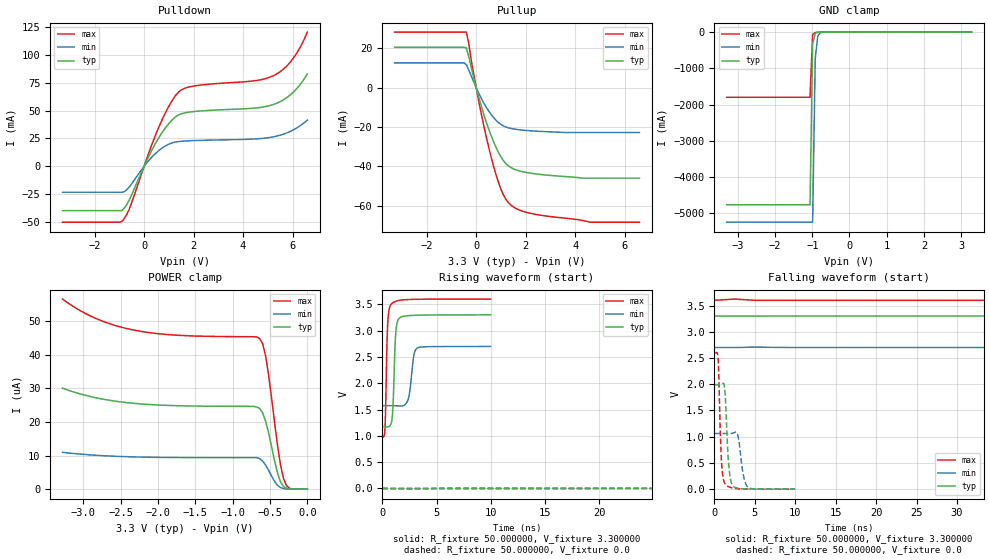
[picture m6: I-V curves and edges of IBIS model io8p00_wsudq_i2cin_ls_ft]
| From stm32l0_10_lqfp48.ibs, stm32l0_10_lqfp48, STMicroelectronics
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|   Model io8p00_wsudq_i2cin_ls_ft
[Model]  io8p00_wsudq_i2cin_ls_ft
Model_type I/O
Polarity   Non-Inverting
Enable   Active-Low
Vinl =   0.990000V
Vinh =   2.310000V
Vmeas =  1.650000V
Cref =   50.000000pF
Rref =   100.000000M
Vref =   0.0V
C_comp   3.020400pF   2.988200pF   3.054500pF
[Temperature Range]   25.000000   0.125000k   -40.000000
[Pullup Reference]   3.300000V   2.700000V   3.600000V
[Pulldown Reference]   0.0V   0.0V   0.0V
[POWER Clamp Reference]   3.300000V   2.700000V   3.600000V
[GND Clamp Reference]   0.0V   0.0V   0.0V
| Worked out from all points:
|   slope of the pulldown table from 0 to 0.495 V, typ, clamps not added: 22.6 ohm
|   slope of the pullup table from 0 to 0.495 V, typ, clamps not added: 23.9 ohm
|   GND clamp passes 1 mA (typ) near -0.64 V on its own axis
|   rising waveform, R_fixture 50.000000, V_fixture 3.300000: 20-80 % time 222ps typ, 369ps min, 183ps max; typ from 1.18 V to 3.3 V
|   rising waveform, R_fixture 50.000000, V_fixture 0.0: 20-80 % time 204ns typ, 426ns min, 99.1ns max; typ from 0 V to 1.99 V
|   falling waveform, R_fixture 50.000000, V_fixture 3.300000: 20-80 % time 191ns typ, 379ns min, 105ns max; typ from 3.3 V to 1.18 V
|   falling waveform, R_fixture 50.000000, V_fixture 0.0: 20-80 % time 405ps typ, 572ps min, 327ps max; typ from 1.99 V to 0 V
[Pulldown]
|Voltage   I(typ)   I(min)   I(max)
-3.3V     -39.83mA   -23.37mA   -50.21mA
-900mV    -39.83mA   -23.37mA   -49.53mA
-600mV    -30.28mA   -18.59mA   -38.45mA
500mV     22.11mA    12.28mA    30.1mA
1V        38.33mA    19.81mA    53.88mA
1.4V      46.1mA     22.18mA    66.72mA
2V        49.07mA    23.02mA    71.93mA
4.4V      52.05mA    24.38mA    76.53mA
5.2V      55.25mA    26.31mA    81.02mA
5.6V      59.18mA    28.57mA    86.57mA
6V        65.78mA    32.24mA    95.97mA
6.6V      82.83mA    41.41mA    120.4mA
[Pullup]
|Voltage   I(typ)   I(min)   I(max)
-3.3V     20.52mA    12.64mA    28.28mA
-400mV    20.25mA    11.77mA    28.28mA
-300mV    15.65mA    8.927mA    22.44mA
-200mV    10.4mA     5.943mA    13.84mA
100mV     -4.685mA   -2.744mA   -6.646mA
600mV     -24.29mA   -13.56mA   -35.12mA
1V        -35.2mA    -18.69mA   -51.63mA
1.2V      -38.62mA   -19.99mA   -56.79mA
1.4V      -40.6mA    -20.72mA   -59.71mA
2.2V      -43.48mA   -21.92mA   -63.91mA
4.6V      -46mA      -22.8mA    -68.41mA
6.6V      -46mA      -22.8mA    -68.41mA
[GND_clamp]
|Voltage   I(typ)   I(min)   I(max)
-3.3V     -4.766A    -5.244A    -1.797A
-1.06V    -4.766A    -5.244A    -1.797A
-990mV    -326.6mA   -5.244A    -67.9mA
-920mV    -28.92mA   -722.1mA   -10.96mA
-850mV    -6.612mA   -104.2mA   -6.532mA
-780mV    -3.464mA   -17.27mA   -4.209mA
-500mV    -57.88uA   -167.8uA   -34.02uA
3.28V     0A         0A         0A
[POWER_clamp]
|Voltage   I(typ)   I(min)   I(max)
-3.28V    30.07uA    10.97uA    56.59uA
-2.84V    27.25uA    10.1uA     50.89uA
-2.32V    25.55uA    9.602uA    47.34uA
-640mV    24.06uA    9.099uA    44.84uA
-600mV    22.76uA    8.364uA    43.37uA
-560mV    20.32uA    7.211uA    39.74uA
-520mV    16.86uA    5.675uA    34.14uA
-400mV    4.841uA    1.145uA    13.1uA
-360mV    2.184uA    477.2nA    7.288uA
-320mV    772.4nA    180.3nA    3.213uA
-240mV    60.03nA    0A         295.3nA
0V        0A         0A         0A
[Ramp]
| variable   typ   min   max
dV/dt_r  1.19496/0.20349u   0.61296/0.42680u   1.55568/98.97032n
dV/dt_f  1.27296/0.19096u   0.63678/0.37937u   1.57856/0.10499u
R_load = 50.000000
[Rising Waveform]
R_fixture= 50.000000
V_fixture= 3.300000
V_fixture_min= 2.700000
V_fixture_max= 3.600000
|time   V(typ)   V(min)   V(max)
0s        1.177V     1.573V     967.3mV
240.2ps   1.176V     1.573V     1.135V
520.5ps   1.173V     1.574V     3.217V
820.8ps   1.244V     1.574V     3.506V
981ps     1.569V     1.574V     3.534V
1.241ns   2.967V     1.572V     3.559V
1.562ns   3.236V     1.568V     3.576V
2.382ns   3.284V     1.699V     3.59V
3.223ns   3.293V     2.67V      3.596V
9.97ns    3.3V       2.7V       3.6V
[Rising Waveform]
R_fixture= 50.000000
V_fixture= 0.0
V_fixture_min= 0.0
V_fixture_max= 0.0
|time   V(typ)   V(min)   V(max)
0s        2.524nV    17.72nV    5.69nV
50.05ns   688.7uV    -21.63uV   86.73mV
100.1ns   75.28mV    12.41uV    913.4mV
162.7ns   438.2mV    6.321mV    1.907V
202.7ns   729.8mV    14.38mV    2.278V
250.2ns   1.059V     49.55mV    2.475V
367.9ns   1.619V     205.5mV    2.576V
503ns     1.881V     442.1mV    2.59V
865.9ns   1.988V     908.5mV    2.592V
1.246us   1.992V     1.062V     2.592V
[Falling Waveform]
R_fixture= 50.000000
V_fixture= 3.300000
V_fixture_min= 2.700000
V_fixture_max= 3.600000
|time   V(typ)   V(min)   V(max)
0s        3.3V       2.7V       3.6V
82.58ns   3.3V       2.7V       3.491V
150.2ns   3.19V      2.7V       2.487V
212.7ns   2.837V     2.697V     1.576V
247.7ns   2.596V     2.687V     1.234V
285.3ns   2.326V     2.665V     1.081V
402.9ns   1.577V     2.534V     992.8mV
513ns     1.314V     2.344V     975.8mV
825.8ns   1.195V     1.79V      967.8mV
1.246us   1.177V     1.573V     967.3mV
[Falling Waveform]
R_fixture= 50.000000
V_fixture= 0.0
V_fixture_min= 0.0
V_fixture_max= 0.0
|time   V(typ)   V(min)   V(max)
0s        1.992V     1.062V     2.592V
440.4ps   1.992V     1.062V     2.509V
860.9ps   1.996V     1.062V     569mV
1.301ns   1.857V     1.062V     105.8mV
1.762ns   477.7mV    1.061V     46.3mV
2.282ns   64.77mV    1.068V     19.81mV
2.883ns   19.1mV     1.029V     7.847mV
3.524ns   7.848mV    313mV      4.636mV
4.164ns   4.058mV    32.89mV    3.148mV
9.97ns    2.524nV    17.72nV    5.69nV
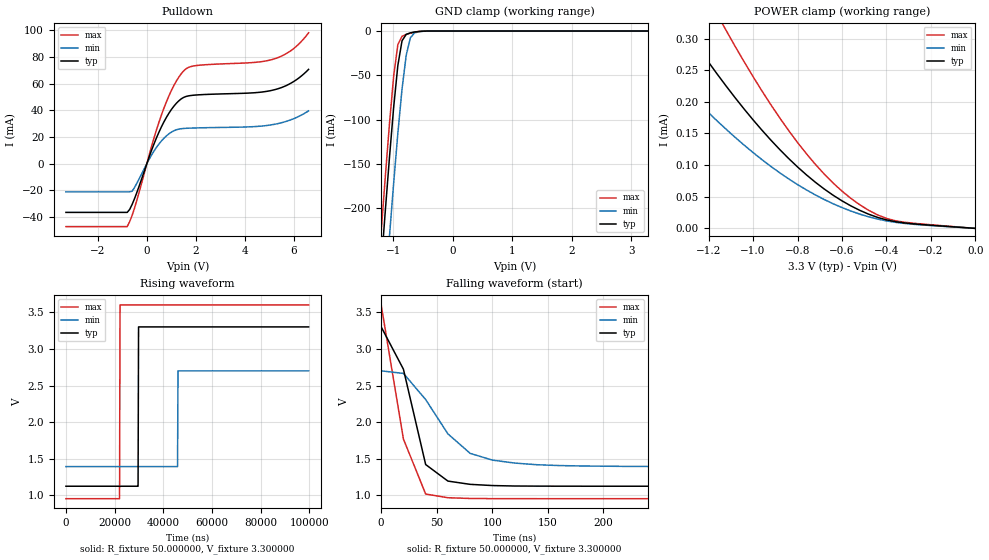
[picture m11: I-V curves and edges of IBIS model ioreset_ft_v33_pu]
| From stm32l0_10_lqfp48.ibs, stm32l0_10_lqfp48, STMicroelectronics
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|   Model ioreset_ft_v33_pu
[Model]  ioreset_ft_v33_pu
Model_type I/O_open_drain
Polarity   Inverting
Enable   Active-High
Vinl =   0.990000V
Vinh =   2.310000V
Vmeas =  1.650000V
Cref =   1.0000000000000001E-7F
Rref =   1.000000k
Vref =   3.300000V
C_comp   2.072900pF   1.973900pF   2.107400pF
[Temperature Range]   25.000000   0.125000k   -40.000000
[Pullup Reference]   3.300000V   2.700000V   3.600000V
[Pulldown Reference]   0.0V   0.0V   0.0V
[POWER Clamp Reference]   3.300000V   2.700000V   3.600000V
[GND Clamp Reference]   0.0V   0.0V   0.0V
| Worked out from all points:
|   slope of the pulldown table from 0 to 0.495 V, typ, clamps not added: 20.9 ohm
|   GND clamp passes 1 mA (typ) near -0.62 V on its own axis
|   rising waveform, R_fixture 50.000000, V_fixture 3.300000: 20-80 % time 120ns typ, 120ns min, 120ns max; typ from 1.12 V to 3.3 V
|   falling waveform, R_fixture 50.000000, V_fixture 3.300000: 20-80 % time 22.8ns typ, 41.3ns min, 21.9ns max; typ from 3.3 V to 1.12 V
[Pulldown]
|Voltage   I(typ)   I(min)   I(max)
-3.3V     -36.46mA   -21.09mA   -47.09mA
-800mV    -36.46mA   -21.09mA   -47.09mA
-600mV    -30.5mA    -20.55mA   -38.69mA
200mV     10.38mA    6.711mA    13.48mA
700mV     31.4mA     19.11mA    41.71mA
1.2V      45.15mA    25.37mA    61.75mA
1.6V      50.35mA    26.5mA     71.06mA
2.1V      51.56mA    26.83mA    73.67mA
4.4V      53.15mA    27.79mA    75.86mA
5.2V      55.35mA    29.47mA    78.49mA
5.9V      60.51mA    33.05mA    84.93mA
6.6V      70.63mA    39.56mA    98mA
[GND_clamp]
|Voltage   I(typ)   I(min)   I(max)
-3.3V     -2.311A    -2.392A    -2.282A
-1.2V     -265.5mA   -356.1mA   -227.2mA
-1.13V    -202.7mA   -292.9mA   -164.1mA
-1.06V    -142.2mA   -231.2mA   -104.1mA
-990mV    -85.98mA   -171.6mA   -50.72mA
-920mV    -38.8mA    -115.5mA   -15.28mA
-850mV    -11.08mA   -65.61mA   -6.001mA
-780mV    -3.782mA   -27.42mA   -3.876mA
-710mV    -2.086mA   -7.69mA    -2.381mA
-640mV    -1.147mA   -2.118mA   -1.22mA
-570mV    -523.9uA   -798.4uA   -476.8uA
3.28V     0A         0A         0A
[POWER_clamp]
|Voltage   I(typ)   I(min)   I(max)
-3.28V    786.1uA    402uA      1.133mA
-1.56V    457.2uA    317.7uA    621.3uA
-1.32V    323.7uA    225.4uA    445.5uA
-1.28V    302.9uA    210.8uA    417.8uA
-1.12V    224.5uA    156.4uA    312.2uA
-960mV    155.3uA    108.7uA    217.3uA
-800mV    97.15uA    69.24uA    135.8uA
-680mV    62.25uA    45.65uA    85.88uA
-560mV    35.54uA    27.42uA    47.39uA
-440mV    17.36uA    14.72uA    21.31uA
-360mV    10.6uA     9.562uA    12.05uA
0V        0A         0A         0A
[Ramp]
| variable   typ   min   max
dV/dt_r  1.30506/59.99448n   0.78426/59.97706n   1.58716/60.00272n
dV/dt_f  1.30506/60.25486n   0.78432/64.35710n   1.58716/60.02224n
R_load = 50.000000
[Rising Waveform]
R_fixture= 50.000000
V_fixture= 3.300000
V_fixture_min= 2.700000
V_fixture_max= 3.600000
|time   V(typ)   V(min)   V(max)
0s        1.125V     1.393V     954.7mV
22.02us   1.125V     1.393V     954.9mV
22.22us   1.125V     1.393V     3.6V
29.63us   1.125V     1.393V     3.6V
29.83us   3.3V       1.393V     3.6V
45.85us   3.3V       1.392V     3.6V
46.05us   3.3V       2.7V       3.6V
99.7us    3.3V       2.7V       3.6V
[Falling Waveform]
R_fixture= 50.000000
V_fixture= 3.300000
V_fixture_min= 2.700000
V_fixture_max= 3.600000
|time   V(typ)   V(min)   V(max)
0s        3.3V       2.7V       3.6V
20.02ns   2.722V     2.665V     1.77V
40.04ns   1.421V     2.308V     1.018V
60.06ns   1.195V     1.84V      967.9mV
80.08ns   1.151V     1.574V     957.8mV
100.1ns   1.134V     1.481V     955.7mV
140.1ns   1.126V     1.418V     954.9mV
180.2ns   1.125V     1.401V     954.7mV
320.3ns   1.125V     1.393V     954.7mV
9.97us    1.125V     1.393V     954.7mV
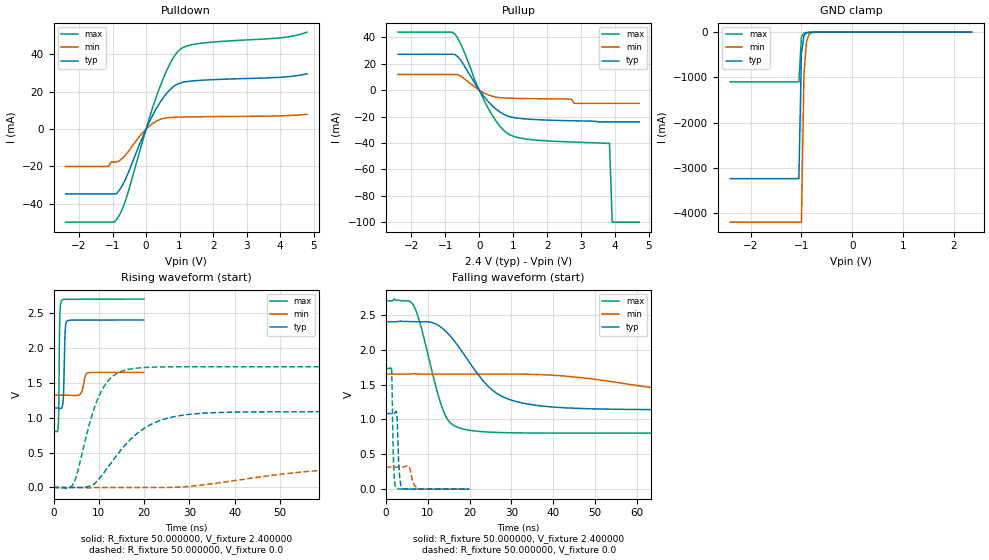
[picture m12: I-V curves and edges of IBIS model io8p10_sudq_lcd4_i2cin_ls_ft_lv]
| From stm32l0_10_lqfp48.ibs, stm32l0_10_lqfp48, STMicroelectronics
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|   Model io8p10_sudq_lcd4_i2cin_ls_ft_lv
[Model]  io8p10_sudq_lcd4_i2cin_ls_ft_lv
Model_type I/O
Polarity   Non-Inverting
Enable   Active-Low
Vinl =   0.720000V
Vinh =   1.680000V
Vmeas =  1.200000V
Cref =   50.000000pF
Rref =   100.000000M
Vref =   0.0V
C_comp   2.470900pF   2.435200pF   2.490500pF
[Temperature Range]   25.000000   0.105000k   -40.000000
[Pullup Reference]   2.400000V   1.650000V   2.700000V
[Pulldown Reference]   0.0V   0.0V   0.0V
[POWER Clamp Reference]   2.400000V   1.650000V   2.700000V
[GND Clamp Reference]   0.0V   0.0V   0.0V
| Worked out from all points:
|   slope of the pulldown table from 0 to 0.36 V, typ, clamps not added: 28.5 ohm
|   slope of the pullup table from 0 to 0.36 V, typ, clamps not added: 32.2 ohm
|   GND clamp passes 1 mA (typ) near -0.64 V on its own axis
|   rising waveform, R_fixture 50.000000, V_fixture 2.400000: 20-80 % time 282ps typ, 634ps min, 193ps max; typ from 1.14 V to 2.4 V
|   rising waveform, R_fixture 50.000000, V_fixture 0.0: 20-80 % time 9.34ns typ, 24.7ns min, 4.81ns max; typ from 0 V to 1.08 V
|   falling waveform, R_fixture 50.000000, V_fixture 2.400000: 20-80 % time 10ns typ, 27ns min, 4.93ns max; typ from 2.4 V to 1.14 V
|   falling waveform, R_fixture 50.000000, V_fixture 0.0: 20-80 % time 457ps typ, 831ps min, 359ps max; typ from 1.08 V to 0 V
[Pulldown]
|Voltage   I(typ)   I(min)   I(max)
-2.4V     -34.7mA    -20mA      -49.82mA
-1.12V    -34.7mA    -20mA      -49.82mA
-1.04V    -34.7mA    -17.6mA    -49.82mA
-880mV    -34.55mA   -17.6mA    -48.46mA
-560mV    -24.65mA   -12.68mA   -35.33mA
0V        326fA      0A         16fA
400mV     13.84mA    5.066mA    22.03mA
720mV     21.25mA    6.254mA    35.26mA
1.04V     24.82mA    6.464mA    43.03mA
1.6V      26.11mA    6.627mA    45.88mA
4V        27.76mA    7.125mA    48.87mA
4.8V      29.63mA    7.94mA     51.96mA
[Pullup]
|Voltage   I(typ)   I(min)   I(max)
-2.4V     27.21mA    11.89mA    44.01mA
-720mV    27.06mA    11.89mA    42.53mA
-480mV    20.06mA    9.352mA    31.11mA
-160mV    6.586mA    3.048mA    9.467mA
240mV     -7.917mA   -3.299mA   -12.65mA
560mV     -15.67mA   -5.497mA   -25.76mA
880mV     -19.92mA   -6.062mA   -33.51mA
1.68V     -22.29mA   -6.449mA   -37.81mA
2.8V      -23.2mA    -10mA      -39.35mA
3.84V     -24mA      -10mA      -40.3mA
3.92V     -24mA      -10mA      -100mA
4.72V     -24mA      -10mA      -100mA
[GND_clamp]
|Voltage   I(typ)   I(min)   I(max)
-2.4V     -3.237A    -4.197A    -1.1A
-1.05V    -3.237A    -4.197A    -1.1A
-1V       -475.5mA   -4.197A    -104.1mA
-950mV    -76.08mA   -935.1mA   -18.44mA
-900mV    -16.57mA   -212.6mA   -9.263mA
-850mV    -6.62mA    -50.88mA   -6.764mA
-800mV    -4.092mA   -13.84mA   -4.994mA
-650mV    -1.07mA    -1.21mA    -1.175mA
2.35V     0A         0A         0A
[POWER_clamp]
|Voltage   I(typ)   I(min)   I(max)
-2.4V     0A         0A         0A
0V        0A         0A         0A
[Ramp]
| variable   typ   min   max
dV/dt_r  0.65070/9.33029n   0.18997/24.67577n   1.03800/4.80098n
dV/dt_f  0.75690/10.02432n   0.19674/26.96447n   1.13815/4.91987n
R_load = 50.000000
[Rising Waveform]
R_fixture= 50.000000
V_fixture= 2.400000
V_fixture_min= 1.650000
V_fixture_max= 2.700000
|time   V(typ)   V(min)   V(max)
0s        1.139V     1.322V     803.1mV
1.041ns   1.138V     1.322V     870.3mV
1.161ns   1.137V     1.322V     1.193V
1.361ns   1.134V     1.322V     2.355V
1.762ns   1.135V     1.322V     2.678V
2.202ns   1.343V     1.322V     2.695V
2.603ns   2.275V     1.322V     2.696V
3.003ns   2.385V     1.322V     2.696V
7.608ns   2.399V     1.642V     2.699V
19.94ns   2.4V       1.65V      2.7V
[Rising Waveform]
R_fixture= 50.000000
V_fixture= 0.0
V_fixture_min= 0.0
V_fixture_max= 0.0
|time   V(typ)   V(min)   V(max)
0s        -771.4nV   -3.33uV    -397.4nV
4.505ns   -901.4uV   98.29uV    66.77mV
8.509ns   33.29mV    -937.1uV   1.038V
11.51ns   245mV      -197.4uV   1.482V
14.01ns   465mV      -200uV     1.634V
18.02ns   749.4mV    -183.2uV   1.708V
25.03ns   990.2mV    551.7uV    1.728V
38.54ns   1.079V     84.42mV    1.73V
81.08ns   1.085V     303.6mV    1.73V
249.2ns   1.085V     316.6mV    1.73V
[Falling Waveform]
R_fixture= 50.000000
V_fixture= 2.400000
V_fixture_min= 1.650000
V_fixture_max= 2.700000
|time   V(typ)   V(min)   V(max)
0s        2.4V       1.65V      2.7V
6.507ns   2.401V     1.657V     2.645V
8.008ns   2.4V       1.651V     2.411V
14.01ns   2.28V      1.65V      1.081V
16.02ns   2.149V     1.65V      921.6mV
21.02ns   1.728V     1.65V      835.2mV
28.53ns   1.309V     1.65V      810.3mV
43.04ns   1.165V     1.62V      803.6mV
92.09ns   1.139V     1.349V     803.1mV
249.2ns   1.139V     1.322V     803.1mV
[Falling Waveform]
R_fixture= 50.000000
V_fixture= 0.0
V_fixture_min= 0.0
V_fixture_max= 0.0
|time   V(typ)   V(min)   V(max)
0s        1.085V     316.6mV    1.73V
1.321ns   1.085V     316.6mV    1.744V
1.441ns   1.085V     316.6mV    1.582V
1.882ns   1.084V     316.6mV    323.6mV
2.442ns   1.117V     316.6mV    19.08mV
2.683ns   1.012V     316.6mV    6.986mV
3.243ns   217.7mV    316.4mV    2.153mV
3.884ns   15.88mV    316.2mV    1.724mV
7.928ns   441.7uV    7.691mV    861.7uV
19.94ns   -771.4nV   -3.33uV    -397.4nV
